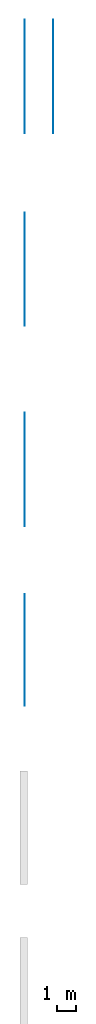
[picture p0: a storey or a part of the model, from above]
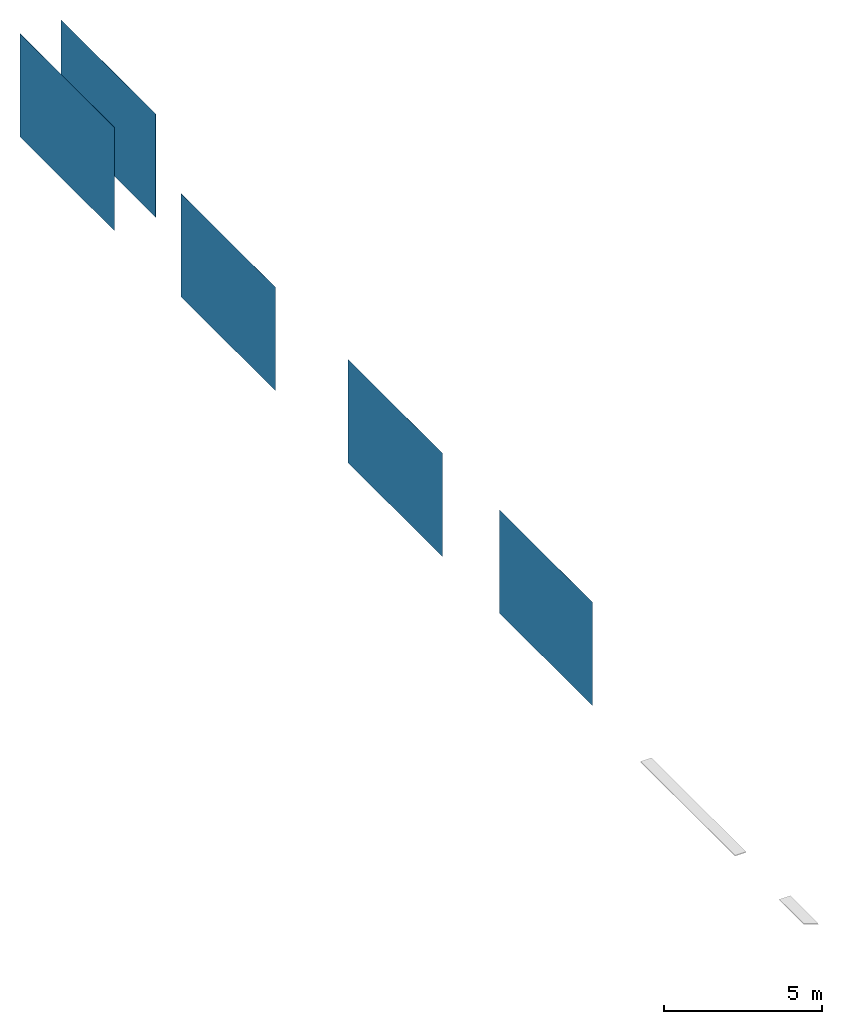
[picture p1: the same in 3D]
Properties of the parts of a building model (IFC2X3)

# File
Description: ViewDefinition [CoordinationView]
File name: Numero
Time: 2019-05-29T14:20:28
Written by: The EXPRESS Data Manager Version 5.02.0100.07 : 28 Aug 2013
Made in: 20150220_1215(x64) - Exporter 16.0.428.0 - Default UI
Comment: STEP Physical File produced by: The EXPRESS Data Manager Version 5.02.0100.07 : 28 Aug 2013 * Module: EDMstepFileFactory/EDMstandAlone * Creation date: Wed May 29 14:20:28 2019 * Host: HP-RS * Database: C:\Users\EKORU_~1\AppData\Local\Temp\{94A0C05F-B792-4B28-9498-05C3A4180E83}\ifc * Database version: 5507 * Database creation date: Wed May 29 14:20:28 2019 * Schema: IFC2X3 * Model: DataRepository.ifc * Model creation date: Wed May 29 14:20:28 2019 * Header model: DataRepository.ifc_HeaderModel * Header model creation date: Wed May 29 14:20:28 2019 * EDMuser: sdai-user * EDMgroup: sdai-group * License ID and type: 5605 : Permanent license. Expiry date: * EDMstepFileFactory options: 020000

# IfcProject, Numero
LongName: Nome; Phase: Stato

# IfcSite, Default
RefLatitude: 41, 47, 59, 999999; RefLongitude: 12, 35, 59, 999999; RefElevation: 0 mm
Altro - Categoria: Informazioni sul progetto; Data di consegna del progetto: Data; Indirizzo del progetto: Immettere l'indirizzo; Nome del cliente: Proprietario; Nome del progetto: Nome; Numero del progetto: Numero; Stato del progetto: Stato

# IfcBuilding
Pset_BuildingCommon - NumberOfStoreys: 1
Altro - Categoria: Informazioni sul progetto; Data di consegna del progetto: Data; Indirizzo del progetto: Immettere l'indirizzo; Nome del cliente: Proprietario; Nome del progetto: Nome; Numero del progetto: Numero; Stato del progetto: Stato

# IfcBuildingStorey, Livello 1
LongName: Livello 1; Elevation: 0 mm
Vincoli - Base quota altimetrica: Punto base progetto; Quota altimetrica: 0 mm
Grafica - Colore: 0; Modello di linea: Centro; Simbolo: Estremità del livello - Cerchio: Estremità del livello - Cerchio; Simbolo a estremità 1 per default: no; Simbolo a estremità 2 per default: yes; Spessore di linea: 1
Dati identità - Nome del tipo: Estremità 8 mm; Strutturale: no; Nome: Livello 1; Piano edificio: yes
Altro - Categoria: Livelli; Nome famiglia: Livello; Famiglia: Livello: Estremità 8 mm; Famiglia e tipo: Livello: Estremità 8 mm; ID tipo: Livello: Estremità 8 mm; Tipo: Livello: Estremità 8 mm
Dimensioni - Altezza di calcolo: 0 mm

# IfcBuildingElementProxy: Adesivo GASBETON, GASBETON Malte:Adesivo GASBETON:141897
In: Livello 1
Type - Material: Adesivo GASBETON
Type - Altro - Categoria: Connessioni strutturali; Nome famiglia: GASBETON Malte
Type - Analisi energetica - Coeff. di diffusione del vapore acqueo (μ): 0; Conducibilità termica a secco: 0.114829; Reazione al fuoco: A1
Type - Analisi strutturale - Adesione (a 28gg): 500000 Pa; Adesione iniziale a taglio: 0 Pa; Resistenza a compressione: 0 Pa; Resistenza a flessione: 0 Pa; Resistenza iniziale a taglio: 0 Pa
Type - Dati identità - Canale YouTube: https://www.youtube.com/user/bacchispa/; Dati tecnici: https://www.gasbeton.it/download; Descrizione: Adesivo per la posa di blocchi in calcestruzzo aerato autoclavato, a base di una speciale schiuma poliuretanica mono-componente basso-espandente formulata per murature a giunto sottile. idraulici, sabbie silicee selezionate, resine sintetiche e speciali additivi. MULTIMALT MALTA ANCORANTE va utilizzata nella realizzazione di murature in blocchi di cls cellulare GASBETON.; Guida all'installazione: https://www.gasbeton.it/wp-content/uploads/2017/11/GASBETON-Guida-alla-progettazione.pdf; Immagine tipo: Immagine raster: Adesivo GASBETON.jpg; Modello: Adesivo GASBETON; Nome del tipo: Adesivo GASBETON; Numero OmniClass: 23.20.15.14; Produttore: Ekoru s.r.l.; Titolo OmniClass: Mortars; URL: https://www.gasbeton.it/download/malte-e-adesivi/; URL prodotto: https://www.gasbeton.it
Type - Generale - Edition Number: 1; Manufacturer Country: Italy; Manufacturer Name: Ekoru s.r.l.; Product Family: Adhesive and mortar
Type - Materiali e finiture - Materiale malta: Adesivo GASBETON
Pset_BuildingElementProxyCommon - Reference: Adesivo GASBETON
Pset_ManufacturerTypeInformation - Manufacturer: Ekoru s.r.l.
Altro - Famiglia: GASBETON Malte: Adesivo GASBETON; Famiglia e tipo: GASBETON Malte: Adesivo GASBETON; ID tipo: GASBETON Malte: Adesivo GASBETON; Tipo: GASBETON Malte: Adesivo GASBETON
Dimensioni - Altezza: 20 mm; Area: 2.528 m2; Larghezza_x: 400 mm; Lunghezza: 6000 mm; Volume: 0.048 m3
Fasi - Fase di creazione: Fase 1
Strutturale - Copriferro armatura: Impostazioni copriferro armatura: Copriferro armatura 1
Vincoli - Offset: 0 mm; Sposta con l'oggetto più vicino: no; Livello: Livello: Livello 1; Host: Livello : Livello 1

# IfcBuildingElementProxy: Malta ancorante IDRO, GASBETON Malte:Malta ancorante IDRO:137478
In: Livello 1
Type - Material: GASBETON Malta Ancorante IDRO
Type - Altro - Categoria: Connessioni strutturali; Nome famiglia: GASBETON Malte
Type - Analisi energetica - Coeff. di diffusione del vapore acqueo (μ): 0; Assorbimento d'acqua: 0.35 kg/m^2•min^0.5; Conducibilità termica a secco: 2.7231; Reazione al fuoco: A1
Type - Analisi strutturale - Adesione (a 28gg): 500000 Pa; Adesione iniziale a taglio: 0 Pa; Resistenza a compressione: 10000000 Pa; Resistenza a flessione: 0 Pa; Resistenza iniziale a taglio: 0 Pa
Type - Dati identità - Canale YouTube: https://www.youtube.com/user/bacchispa/; Dati tecnici: https://www.gasbeton.it/download; Descrizione: MALTA NCORANTE IDROFUGA PREDOSATA per l’allettamento della prima fila di blocchi in calcestruzzo Aerato Autoclavato (AAC) per murature portanti e non portanti, sia in interno che in esterno, idonea per evitare la risalita di umidità per capillarità anche senza impiego di guaine impermeabilizzanti.; Guida all'installazione: https://www.gasbeton.it/wp-content/uploads/2017/11/GASBETON-Guida-alla-progettazione.pdf; Immagine tipo: Immagine raster: GASBETON Malta ancorante IDRO.jpg; Modello: GASBETON Malta ancorante IDRO; Nome del tipo: Malta ancorante IDRO; Numero OmniClass: 23.20.15.14; Produttore: Ekoru s.r.l.; Titolo OmniClass: Mortars; URL: https://www.gasbeton.it/download/malte-e-adesivi/; URL prodotto: https://www.gasbeton.it
Type - Generale - Edition Number: 1; Manufacturer Country: Italy; Manufacturer Name: Ekoru s.r.l.; Product Family: Adhesive and mortar
Type - Materiali e finiture - Materiale malta: GASBETON Malta Ancorante IDRO
Pset_BuildingElementProxyCommon - Reference: Malta ancorante IDRO
Pset_ManufacturerTypeInformation - Manufacturer: Ekoru s.r.l.
Altro - Famiglia: GASBETON Malte: Malta ancorante IDRO; Famiglia e tipo: GASBETON Malte: Malta ancorante IDRO; ID tipo: GASBETON Malte: Malta ancorante IDRO; Tipo: GASBETON Malte: Malta ancorante IDRO
Dimensioni - Altezza: 30 mm; Area: 2.592 m2; Larghezza_x: 400 mm; Lunghezza: 6000 mm; Volume: 0.072 m3
Fasi - Fase di creazione: Fase 1
Strutturale - Copriferro armatura: Impostazioni copriferro armatura: Copriferro armatura 1
Vincoli - Offset: 0 mm; Sposta con l'oggetto più vicino: no; Host: Livello : Livello 1; Livello: Livello: Livello 1

# IfcBuildingElementProxy: Multimalt, GASBETON Malte:Multimalt:128211
In: Livello 1
Type - Material: GASBETON Multimalt
Type - Altro - Categoria: Connessioni strutturali; Nome famiglia: GASBETON Malte
Type - Analisi energetica - Coeff. di diffusione del vapore acqueo (μ): 0; Conducibilità termica a secco: 1.27953; Reazione al fuoco: A1
Type - Analisi strutturale - Adesione (a 28gg): 0 Pa; Adesione iniziale a taglio: 150000 Pa; Resistenza a compressione: 10000000 Pa; Resistenza a flessione: 0 Pa; Resistenza iniziale a taglio: 0 Pa
Type - Dati identità - Canale YouTube: https://www.youtube.com/user/bacchispa/; Dati tecnici: https://www.gasbeton.it/download; Descrizione: MULTIMALT MALTA ANCORANTE è una polvere premiscelata di colore grigio a base di leganti idraulici, sabbie silicee selezionate, resine sintetiche e speciali additivi. MULTIMALT MALTA ANCORANTE va utilizzata nella realizzazione di murature in blocchi di cls cellulare GASBETON.; Guida all'installazione: https://www.gasbeton.it/wp-content/uploads/2017/11/GASBETON-Guida-alla-progettazione.pdf; Modello: GASBETON Multimalt - M10; Nome del tipo: Multimalt; Numero OmniClass: 23.20.15.14; Produttore: Ekoru s.r.l.; Titolo OmniClass: Mortars; URL: https://www.gasbeton.it/download/malte-e-adesivi/; URL prodotto: https://www.gasbeton.it
Type - Generale - Edition Number: 1; Manufacturer Country: Italy; Manufacturer Name: Ekoru s.r.l.; Product Family: Adhesive and mortar
Type - Materiali e finiture - Materiale malta: GASBETON Multimalt
Pset_BuildingElementProxyCommon - Reference: Multimalt
Pset_ManufacturerTypeInformation - Manufacturer: Ekoru s.r.l.
Altro - Famiglia: GASBETON Malte: Multimalt; Famiglia e tipo: GASBETON Malte: Multimalt; ID tipo: GASBETON Malte: Multimalt; Tipo: GASBETON Malte: Multimalt
Dimensioni - Altezza: 30 mm; Area: 2.592 m2; Larghezza_x: 400 mm; Lunghezza: 6000 mm; Volume: 0.072 m3
Fasi - Fase di creazione: Fase 1
Strutturale - Copriferro armatura: Impostazioni copriferro armatura: Copriferro armatura 1
Vincoli - Host: Livello : Livello 1; Livello: Livello: Livello 1; Offset: 0 mm; Sposta con l'oggetto più vicino: no

# IfcWallStandardCase: Muro di base:GASBETON IncollaRasa M10, Muro di base:GASBETON IncollaRasa M10:128485
In: Livello 1
Type - PredefinedType: STANDARD; Material: GASBETON Incollarasa - M10 5 mm
Type - Altro - Categoria: Muri; Nome famiglia: Muro di base
Type - Costruzione - Funzione: Esterno; Ripiegatura agli inserti: Non ripiegare; Ripiegatura alle estremità: Nessuno; Larghezza: 5 mm
Type - Dati identità - Immagine tipo: Immagine raster: GASBETON Incollarasa.jpg; Descrizione: Malta da muratura di colore bianco a prestazione garantita, a strato sottile (T), di classe M5/M10, per utilizzo in interni ed esterni conforme alla normativa UNI EN 998-2 e UNI EN 998-1. garantita, a strato sottile (T), di classe M5/M10, per utilizzo in interni ed esterni conforme alla normativa Malta da muratura di colore bianco a prestazione garantita, a strato sottile (T), di classe M5/M10, per utilizzo in interni ed esterni conforme alla normativa UNI EN 998-2 e UNI EN 998-1.; Modello: M10; Nome del tipo: GASBETON IncollaRasa M10; Produttore: Ekoru s.r.l.; URL: https://www.gasbeton.it/download/malte-e-adesivi/
Type - Grafica - Colore del retino a dettaglio basso: 12632256
Type - Proprietà analitiche - Ruvidità: 3; Assorbimento: 0.7; Coefficiente di scambio termico (U): 78; Massa termica: 6240; Resistenza termica (R): 0.0128205
Altro - Famiglia: Muro di base: GASBETON IncollaRasa M10; Famiglia e tipo: Muro di base: GASBETON IncollaRasa M10; ID tipo: Muro di base: GASBETON IncollaRasa M10; Tipo: Muro di base: GASBETON IncollaRasa M10
Dimensioni - Area: 24 m2; Lunghezza: 6000 mm; Volume: 0.12 m3
Fasi - Fase di creazione: Fase 1
Strutturale - Attiva modello analitico: no; Strutturale: no; Utilizzo strutturale: Non portante
Vincoli - Delimita il locale: yes; Distanza estensione base: 0 mm; Distanza estensione superiore: 0 mm; La base è associata: no; La parte superiore è associata: no; Linea di ubicazione: Linea d'asse del muro; Offset base: 0 mm; Offset superiore: 0 mm; Relativo a massa: no; Vincolo di base: Livello: Livello 1; Altezza non collegata: 4000 mm
Pset_WallCommon - LoadBearing: no; ExtendToStructure: no; IsExternal: yes; Reference: GASBETON IncollaRasa M10; ThermalTransmittance: 78 kg/K/s3
Pset_ManufacturerTypeInformation - Manufacturer: Ekoru s.r.l.

# IfcWallStandardCase: Muro di base:GASBETON IncollaRasa M5, Muro di base:GASBETON IncollaRasa M5:128344
In: Livello 1
Type - PredefinedType: STANDARD; Material: GASBETON Incollarasa - M5 5 mm
Type - Altro - Categoria: Muri; Nome famiglia: Muro di base
Type - Costruzione - Funzione: Esterno; Larghezza: 5 mm; Ripiegatura agli inserti: Non ripiegare; Ripiegatura alle estremità: Nessuno
Type - Dati identità - Descrizione: Malta da muratura di colore bianco a prestazione garantita, a strato sottile (T), di classe M5/M10, per utilizzo in interni ed esterni conforme alla normativa UNI EN 998-2 e UNI EN 998-1. garantita, a strato sottile (T), di classe M5/M10, per utilizzo in interni ed esterni conforme alla normativa Malta da muratura di colore bianco a prestazione garantita, a strato sottile (T), di classe M5/M10, per utilizzo in interni ed esterni conforme alla normativa UNI EN 998-2 e UNI EN 998-1.; Immagine tipo: Immagine raster: GASBETON Incollarasa.jpg; Modello: M5; Nome del tipo: GASBETON IncollaRasa M5; Produttore: Ekoru s.r.l.; URL: https://www.gasbeton.it/download/malte-e-adesivi/
Type - Grafica - Colore del retino a dettaglio basso: 0
Type - Proprietà analitiche - Assorbimento: 0.7; Coefficiente di scambio termico (U): 78; Massa termica: 6240; Resistenza termica (R): 0.0128205; Ruvidità: 3
Altro - Famiglia: Muro di base: GASBETON IncollaRasa M5; Famiglia e tipo: Muro di base: GASBETON IncollaRasa M5; ID tipo: Muro di base: GASBETON IncollaRasa M5; Tipo: Muro di base: GASBETON IncollaRasa M5
Dimensioni - Area: 24 m2; Lunghezza: 6000 mm; Volume: 0.12 m3
Fasi - Fase di creazione: Fase 1
Strutturale - Attiva modello analitico: no; Strutturale: no; Utilizzo strutturale: Non portante
Vincoli - Altezza non collegata: 4000 mm; Delimita il locale: yes; Distanza estensione base: 0 mm; Distanza estensione superiore: 0 mm; La base è associata: no; La parte superiore è associata: no; Linea di ubicazione: Linea d'asse del muro; Offset base: 0 mm; Offset superiore: 0 mm; Relativo a massa: no; Vincolo di base: Livello: Livello 1
Pset_WallCommon - Reference: GASBETON IncollaRasa M5; LoadBearing: no; ExtendToStructure: no; IsExternal: yes; ThermalTransmittance: 78 kg/K/s3
Pset_ManufacturerTypeInformation - Manufacturer: Ekoru s.r.l.

# IfcWallStandardCase: Muro di base:GASBETON Multicem, Muro di base:GASBETON Multicem:128608
In: Livello 1
Type - PredefinedType: STANDARD; Material: GASBETON Incollarasa - M10 2 mm
Type - Altro - Categoria: Muri; Nome famiglia: Muro di base
Type - Costruzione - Funzione: Esterno; Ripiegatura agli inserti: Non ripiegare; Ripiegatura alle estremità: Nessuno; Larghezza: 2 mm
Type - Dati identità - Descrizione: Malta da muratura di colore bianco a prestazione garantita, a strato sottile (T), di classe M5/M10, per utilizzo in interni ed esterni conforme alla normativa UNI EN 998-2 e UNI EN 998-1. garantita, a strato sottile (T), di classe M5/M10, per utilizzo in interni ed esterni conforme alla normativa Malta da muratura di colore bianco a prestazione garantita, a strato sottile (T), di classe M5/M10, per utilizzo in interni ed esterni conforme alla normativa UNI EN 998-2 e UNI EN 998-1.; Immagine tipo: Immagine raster: GASBETON Multicem.jpg; Modello: M10; Nome del tipo: GASBETON Multicem; Produttore: Ekoru s.r.l.; URL: https://www.gasbeton.it/download/malte-e-adesivi/
Type - Grafica - Colore del retino a dettaglio basso: 8684676
Type - Proprietà analitiche - Ruvidità: 3; Assorbimento: 0.7; Coefficiente di scambio termico (U): 195; Massa termica: 2496; Resistenza termica (R): 0.00512821
Altro - Famiglia: Muro di base: GASBETON Multicem; Famiglia e tipo: Muro di base: GASBETON Multicem; ID tipo: Muro di base: GASBETON Multicem; Tipo: Muro di base: GASBETON Multicem
Dimensioni - Area: 24 m2; Lunghezza: 6000 mm; Volume: 0.048 m3
Fasi - Fase di creazione: Fase 1
Strutturale - Attiva modello analitico: no; Strutturale: no; Utilizzo strutturale: Non portante
Vincoli - Delimita il locale: yes; Distanza estensione base: 0 mm; Distanza estensione superiore: 0 mm; La base è associata: no; La parte superiore è associata: no; Linea di ubicazione: Linea d'asse del muro; Offset base: 0 mm; Offset superiore: 0 mm; Relativo a massa: no; Vincolo di base: Livello: Livello 1; Altezza non collegata: 4000 mm
Pset_WallCommon - LoadBearing: no; ExtendToStructure: no; IsExternal: yes; Reference: GASBETON Multicem; ThermalTransmittance: 195 kg/K/s3
Pset_ManufacturerTypeInformation - Manufacturer: Ekoru s.r.l.

# IfcWallStandardCase: Muro di base:GASBETON Multiraso Esterni, Muro di base:GASBETON Multiraso Esterni:128693
In: Livello 1
Type - PredefinedType: STANDARD; Material: GASBETON Multiraso esterni 2 mm
Type - Altro - Categoria: Muri; Nome famiglia: Muro di base
Type - Costruzione - Funzione: Esterno; Ripiegatura agli inserti: Non ripiegare; Ripiegatura alle estremità: Nessuno; Larghezza: 2 mm
Type - Dati identità - Descrizione: Finitura premiscelata idrofugata fibrorinforzata a base di calce naturale e leganti idraulici adatta per la finitura di superfici esterne di edifici vecchi e nuovi ad elevato livello qualitativo costante, prodotta con impianto computerizzato, da applicare a mano. Utilizzata come finitura si applica su qualsiasi superficie esterna da rifinire. Non fessura, non distacca è traspirante e resistente all’urto. Costituisce il fondo ideale per rivestimento superficiale quale pitture ai silicati silossanici e acril-silossanici; Immagine tipo: Immagine raster: GASBETON Multiraso Esterni.jpg; Modello: Multiraso Ext; Nome del tipo: GASBETON Multiraso Esterni; Produttore: Ekoru s.r.l.; URL: https://www.gasbeton.it/download/malte-e-adesivi/
Type - Grafica - Colore del retino a dettaglio basso: 15329769
Type - Proprietà analitiche - Ruvidità: 3; Assorbimento: 0.7; Coefficiente di scambio termico (U): 175; Massa termica: 2304; Resistenza termica (R): 0.00571429
Altro - Famiglia: Muro di base: GASBETON Multiraso Esterni; Famiglia e tipo: Muro di base: GASBETON Multiraso Esterni; ID tipo: Muro di base: GASBETON Multiraso Esterni; Tipo: Muro di base: GASBETON Multiraso Esterni
Dimensioni - Area: 24 m2; Lunghezza: 6000 mm; Volume: 0.048 m3
Fasi - Fase di creazione: Fase 1
Strutturale - Attiva modello analitico: no; Strutturale: no; Utilizzo strutturale: Non portante
Vincoli - Delimita il locale: yes; Distanza estensione base: 0 mm; Distanza estensione superiore: 0 mm; La base è associata: no; La parte superiore è associata: no; Linea di ubicazione: Linea d'asse del muro; Offset base: 0 mm; Offset superiore: 0 mm; Relativo a massa: no; Vincolo di base: Livello: Livello 1; Altezza non collegata: 4000 mm
Pset_WallCommon - LoadBearing: no; ExtendToStructure: no; IsExternal: yes; Reference: GASBETON Multiraso Esterni; ThermalTransmittance: 175 kg/K/s3
Pset_ManufacturerTypeInformation - Manufacturer: Ekoru s.r.l.

# IfcWallStandardCase: Muro di base:GASBETON Multiraso Interni, Muro di base:GASBETON Multiraso Interni:128761
In: Livello 1
Type - PredefinedType: STANDARD; Material: GASBETON Multiraso interni 2 mm
Type - Altro - Categoria: Muri; Nome famiglia: Muro di base
Type - Costruzione - Funzione: Esterno; Ripiegatura agli inserti: Non ripiegare; Ripiegatura alle estremità: Nessuno; Larghezza: 2 mm
Type - Dati identità - Descrizione: Rasante premiscelato da applicarsi direttamente su superfici interne. Adatto per la finitura liscia di intonaci tradizionali o premiscelati sia a base di calce e cemento che di calce e gesso, come rasante di superficie piane come blocchi in cemento cellulare e pannelli di gesso, come finitura a stucco su vecchie murature dopo l’eliminazione di vecchie pitture o parati, per rappezzi a zona e come collante per il posizionamento di gessolino e cornici in genere.; Immagine tipo: Immagine raster: GASBETON Multiraso Interni.jpg; Modello: Multiraso Ext; Nome del tipo: GASBETON Multiraso Interni; Produttore: Ekoru s.r.l.; URL: https://www.gasbeton.it/download/malte-e-adesivi/
Type - Grafica - Colore del retino a dettaglio basso: 15329769
Type - Proprietà analitiche - Ruvidità: 3; Assorbimento: 0.7; Coefficiente di scambio termico (U): 110; Massa termica: 1344; Resistenza termica (R): 0.00909091
Altro - Famiglia: Muro di base: GASBETON Multiraso Interni; Famiglia e tipo: Muro di base: GASBETON Multiraso Interni; ID tipo: Muro di base: GASBETON Multiraso Interni; Tipo: Muro di base: GASBETON Multiraso Interni
Dimensioni - Area: 23.6 m2; Lunghezza: 5900 mm; Volume: 0.0472 m3
Fasi - Fase di creazione: Fase 1
Strutturale - Attiva modello analitico: no; Strutturale: no; Utilizzo strutturale: Non portante
Vincoli - Delimita il locale: yes; Distanza estensione base: 0 mm; Distanza estensione superiore: 0 mm; La base è associata: no; La parte superiore è associata: no; Linea di ubicazione: Linea d'asse del muro; Offset base: 0 mm; Offset superiore: 0 mm; Relativo a massa: no; Vincolo di base: Livello: Livello 1; Altezza non collegata: 4000 mm
Pset_WallCommon - LoadBearing: no; ExtendToStructure: no; IsExternal: yes; Reference: GASBETON Multiraso Interni; ThermalTransmittance: 110 kg/K/s3
Pset_ManufacturerTypeInformation - Manufacturer: Ekoru s.r.l.
